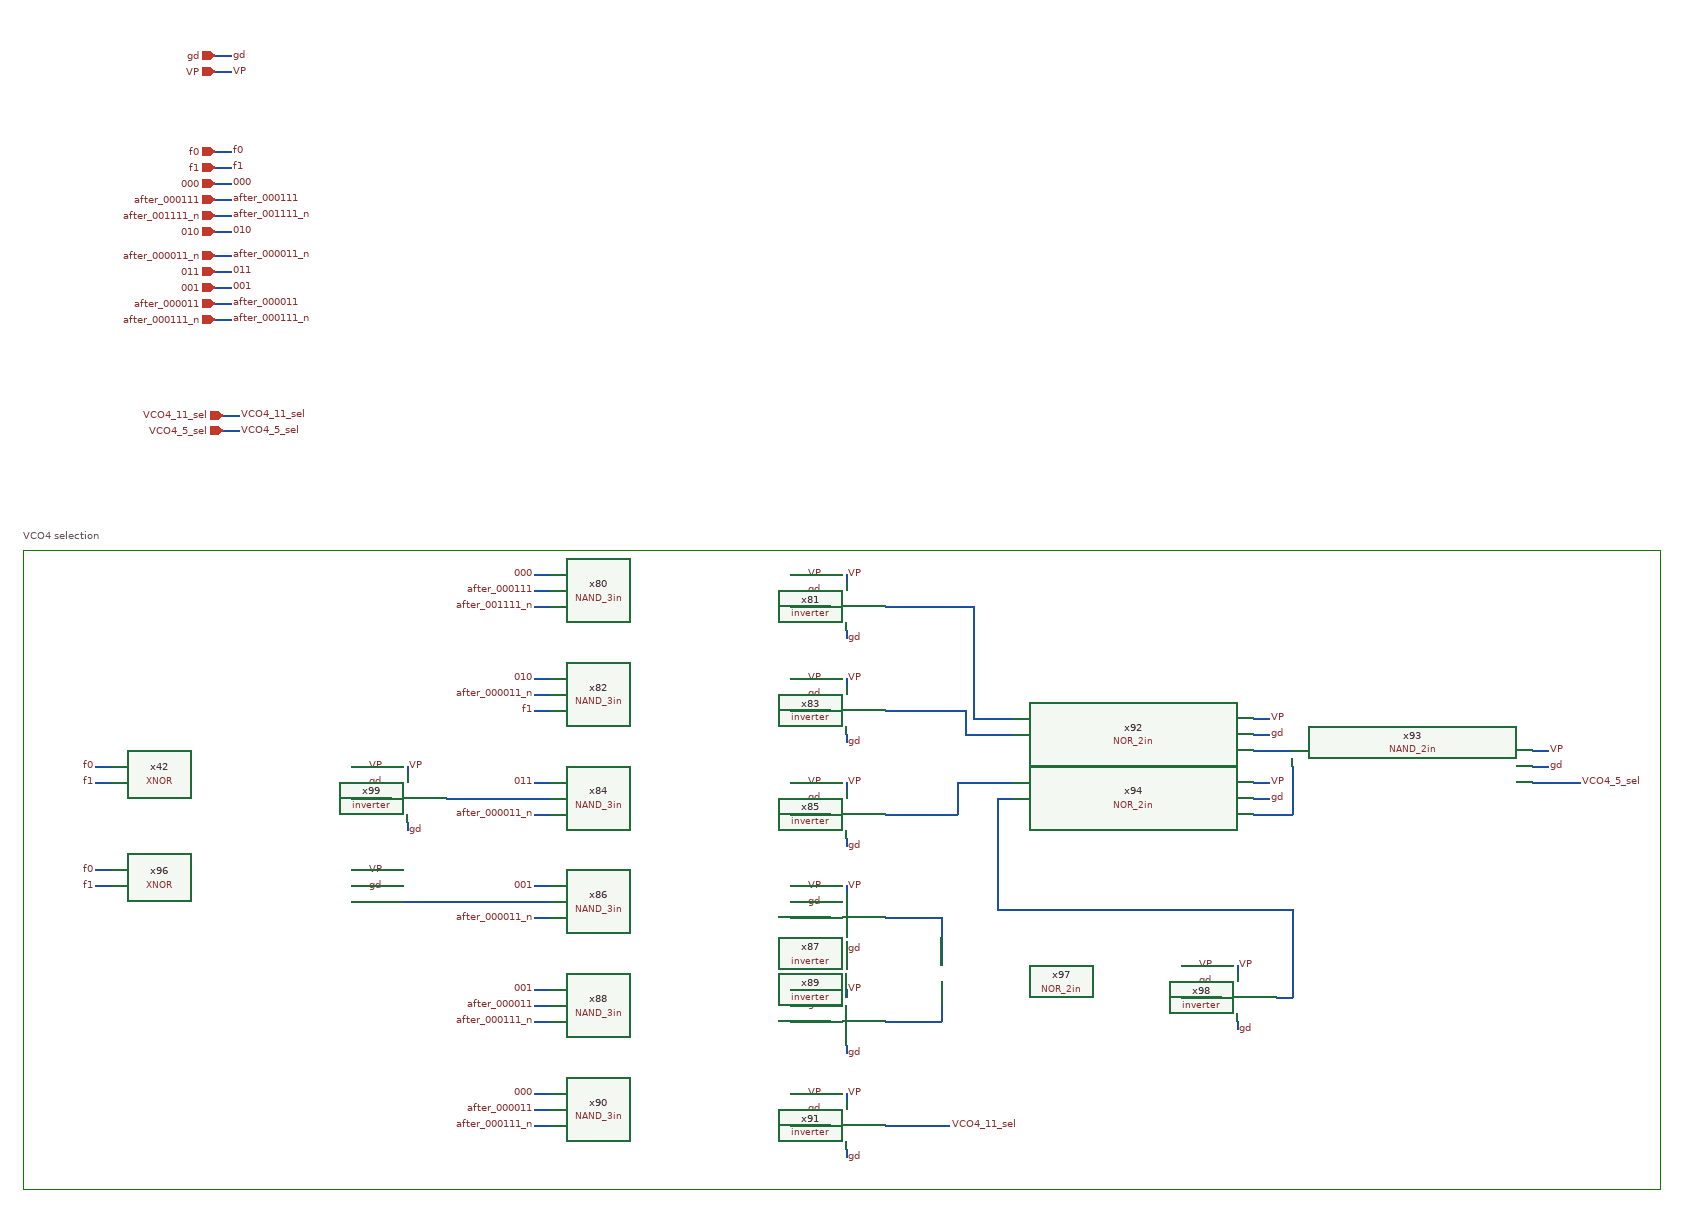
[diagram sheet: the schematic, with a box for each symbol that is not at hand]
v {xschem version=3.4.8RC file_version=1.3}
G {}
K {}
V {}
S {}
F {}
E {}
L 4 1530 -1920 1530 -1580 {}
L 4 1530 -2260 1530 -1920 {}
L 4 1530 -2260 1870 -2260 {}
L 4 1870 -2260 2210 -2260 {}
L 4 2210 -2260 2550 -2260 {}
L 4 2530 -2260 2870 -2260 {}
L 4 2240 -2260 2580 -2260 {}
L 4 2580 -2260 2920 -2260 {}
L 4 2920 -2260 3260 -2260 {}
L 4 3240 -2260 3580 -2260 {}
L 4 1530 -1460 1870 -1460 {}
L 4 1870 -1460 2210 -1460 {}
L 4 2210 -1460 2550 -1460 {}
L 4 2530 -1460 2870 -1460 {}
L 4 2920 -1460 3260 -1460 {}
L 4 3240 -1460 3580 -1460 {}
L 4 2780 -1460 3120 -1460 {}
L 4 1530 -1800 1530 -1460 {}
L 4 3580 -1920 3580 -1580 {}
L 4 3580 -2260 3580 -1920 {}
L 4 3580 -1800 3580 -1460 {}
T {VCO4 selection} 1530 -2290 0 0 0.4 0.4 {}
N 2490 -2210 2510 -2210 {lab=gd}
N 2490 -2230 2510 -2230 {lab=VP}
N 2560 -2160 2560 -2150 {lab=gd}
N 2560 -2230 2560 -2220 {lab=VP}
N 2490 -2190 2540 -2190 {lab=#net1}
N 2610 -2190 2720 -2190 {lab=#net2}
N 2170 -2230 2190 -2230 {lab=000}
N 2170 -2190 2190 -2190 {lab=after_001111_n}
N 2170 -2210 2190 -2210 {lab=after_000111}
N 2490 -2080 2510 -2080 {lab=gd}
N 2490 -2100 2510 -2100 {lab=VP}
N 2560 -2030 2560 -2020 {lab=gd}
N 2560 -2100 2560 -2090 {lab=VP}
N 2490 -2060 2540 -2060 {lab=#net3}
N 2610 -2060 2710 -2060 {lab=#net4}
N 2170 -2100 2190 -2100 {lab=010}
N 2170 -2060 2190 -2060 {lab=f1}
N 2170 -2080 2190 -2080 {lab=after_000011_n}
N 2490 -1950 2510 -1950 {lab=gd}
N 2490 -1970 2510 -1970 {lab=VP}
N 2560 -1900 2560 -1890 {lab=gd}
N 2560 -1970 2560 -1960 {lab=VP}
N 2490 -1930 2540 -1930 {lab=#net5}
N 2610 -1930 2700 -1930 {lab=#net6}
N 2170 -1970 2190 -1970 {lab=011}
N 2170 -1930 2190 -1930 {lab=after_000011_n}
N 2490 -1820 2510 -1820 {lab=gd}
N 2490 -1840 2510 -1840 {lab=VP}
N 2560 -1770 2560 -1760 {lab=gd}
N 2560 -1840 2560 -1830 {lab=VP}
N 2490 -1800 2540 -1800 {lab=#net7}
N 2170 -1840 2190 -1840 {lab=001}
N 2170 -1800 2190 -1800 {lab=after_000011_n}
N 2490 -1690 2510 -1690 {lab=gd}
N 2490 -1710 2510 -1710 {lab=VP}
N 2560 -1640 2560 -1630 {lab=gd}
N 2560 -1710 2560 -1700 {lab=VP}
N 2490 -1670 2540 -1670 {lab=#net8}
N 2170 -1710 2190 -1710 {lab=001}
N 2170 -1670 2190 -1670 {lab=after_000111_n}
N 2170 -1690 2190 -1690 {lab=after_000011}
N 2490 -1560 2510 -1560 {lab=gd}
N 2490 -1580 2510 -1580 {lab=VP}
N 2560 -1510 2560 -1500 {lab=gd}
N 2560 -1580 2560 -1570 {lab=VP}
N 2490 -1540 2540 -1540 {lab=#net9}
N 2610 -1540 2690 -1540 {lab=VCO4_11_sel}
N 2170 -1580 2190 -1580 {lab=000}
N 2170 -1540 2190 -1540 {lab=after_000111_n}
N 2170 -1560 2190 -1560 {lab=after_000011}
N 3070 -2030 3090 -2030 {lab=gd}
N 3070 -2050 3090 -2050 {lab=VP}
N 3070 -2010 3120 -2010 {lab=#net10}
N 3070 -1950 3090 -1950 {lab=gd}
N 3070 -1970 3090 -1970 {lab=VP}
N 3070 -1930 3120 -1930 {lab=#net11}
N 2750 -1950 2770 -1950 {lab=#net12}
N 3120 -1990 3120 -1930 {lab=#net11}
N 3420 -1990 3440 -1990 {lab=gd}
N 3420 -2010 3440 -2010 {lab=VP}
N 2980 -1720 3000 -1720 {lab=gd}
N 2980 -1740 3000 -1740 {lab=VP}
N 3050 -1670 3050 -1660 {lab=gd}
N 3050 -1740 3050 -1730 {lab=VP}
N 2980 -1700 3030 -1700 {lab=#net13}
N 3100 -1700 3120 -1700 {lab=#net12}
N 2680 -1800 2680 -1740 {lab=#net14}
N 2610 -1800 2680 -1800 {lab=#net14}
N 2680 -1720 2680 -1670 {lab=#net15}
N 2610 -1670 2680 -1670 {lab=#net15}
N 2710 -2060 2710 -2030 {lab=#net4}
N 2710 -2030 2770 -2030 {lab=#net4}
N 2720 -2050 2770 -2050 {lab=#net2}
N 2720 -2190 2720 -2050 {lab=#net2}
N 2700 -1970 2700 -1930 {lab=#net6}
N 2700 -1970 2770 -1970 {lab=#net6}
N 2750 -1950 2750 -1810 {lab=#net12}
N 2750 -1810 3120 -1810 {lab=#net12}
N 3120 -1810 3120 -1700 {lab=#net12}
N 3420 -1970 3480 -1970 {lab=VCO4_5_sel}
N 1940 -1840 1960 -1840 {lab=gd}
N 1940 -1860 1960 -1860 {lab=VP}
N 1940 -1970 1960 -1970 {lab=gd}
N 1940 -1990 1960 -1990 {lab=VP}
N 2010 -1920 2010 -1910 {lab=gd}
N 2010 -1990 2010 -1980 {lab=VP}
N 1940 -1950 1990 -1950 {lab=#net16}
N 1620 -1990 1640 -1990 {lab=f0}
N 1620 -1970 1640 -1970 {lab=f1}
N 1940 -1820 2190 -1820 {lab=#net17}
N 2060 -1950 2190 -1950 {lab=#net18}
N 1620 -1860 1640 -1860 {lab=f0}
N 1620 -1840 1640 -1840 {lab=f1}
N 1770 -2880 1790 -2880 {lab=gd}
N 1770 -2860 1790 -2860 {lab=VP}
N 1770 -2760 1790 -2760 {lab=f0}
N 1770 -2740 1790 -2740 {lab=f1}
N 1780 -2410 1800 -2410 {lab=VCO4_5_sel}
N 1780 -2430 1800 -2430 {lab=VCO4_11_sel}
N 1770 -2720 1790 -2720 {lab=000}
N 1770 -2700 1790 -2700 {lab=after_000111}
N 1770 -2680 1790 -2680 {lab=after_001111_n}
N 1770 -2660 1790 -2660 {lab=010}
N 1770 -2630 1790 -2630 {lab=after_000011_n}
N 1770 -2610 1790 -2610 {lab=011}
N 1770 -2590 1790 -2590 {lab=001}
N 1770 -2570 1790 -2570 {lab=after_000011}
N 1770 -2550 1790 -2550 {lab=after_000111_n}
C {NAND_3in.sym} 2340 -2210 0 0 {name=x80}
C {lab_wire.sym} 2510 -2230 2 0 {name=p327 sig_type=std_logic lab=VP}
C {lab_wire.sym} 2510 -2210 2 0 {name=p328 sig_type=std_logic lab=gd}
C {inverter.sym} 2560 -2190 0 0 {name=x81}
C {lab_wire.sym} 2560 -2230 0 1 {name=p329 sig_type=std_logic lab=VP}
C {lab_wire.sym} 2560 -2150 2 0 {name=p330 sig_type=std_logic lab=gd}
C {NAND_3in.sym} 2340 -2080 0 0 {name=x82}
C {lab_wire.sym} 2510 -2100 2 0 {name=p331 sig_type=std_logic lab=VP}
C {lab_wire.sym} 2510 -2080 2 0 {name=p332 sig_type=std_logic lab=gd}
C {inverter.sym} 2560 -2060 0 0 {name=x83}
C {lab_wire.sym} 2560 -2100 0 1 {name=p333 sig_type=std_logic lab=VP}
C {lab_wire.sym} 2560 -2020 2 0 {name=p334 sig_type=std_logic lab=gd}
C {NAND_3in.sym} 2340 -1950 0 0 {name=x84}
C {lab_wire.sym} 2510 -1970 2 0 {name=p335 sig_type=std_logic lab=VP}
C {lab_wire.sym} 2510 -1950 2 0 {name=p336 sig_type=std_logic lab=gd}
C {inverter.sym} 2560 -1930 0 0 {name=x85}
C {lab_wire.sym} 2560 -1970 0 1 {name=p337 sig_type=std_logic lab=VP}
C {lab_wire.sym} 2560 -1890 2 0 {name=p338 sig_type=std_logic lab=gd}
C {NAND_3in.sym} 2340 -1820 0 0 {name=x86}
C {lab_wire.sym} 2510 -1840 2 0 {name=p339 sig_type=std_logic lab=VP}
C {lab_wire.sym} 2510 -1820 2 0 {name=p340 sig_type=std_logic lab=gd}
C {inverter.sym} 2560 -1800 0 0 {name=x87}
C {lab_wire.sym} 2560 -1840 0 1 {name=p341 sig_type=std_logic lab=VP}
C {lab_wire.sym} 2560 -1760 2 0 {name=p342 sig_type=std_logic lab=gd}
C {NAND_3in.sym} 2340 -1690 0 0 {name=x88}
C {lab_wire.sym} 2510 -1710 2 0 {name=p343 sig_type=std_logic lab=VP}
C {lab_wire.sym} 2510 -1690 2 0 {name=p344 sig_type=std_logic lab=gd}
C {inverter.sym} 2560 -1670 0 0 {name=x89}
C {lab_wire.sym} 2560 -1710 0 1 {name=p345 sig_type=std_logic lab=VP}
C {lab_wire.sym} 2560 -1630 2 0 {name=p346 sig_type=std_logic lab=gd}
C {NAND_3in.sym} 2340 -1560 0 0 {name=x90}
C {lab_wire.sym} 2510 -1580 2 0 {name=p347 sig_type=std_logic lab=VP}
C {lab_wire.sym} 2510 -1560 2 0 {name=p348 sig_type=std_logic lab=gd}
C {inverter.sym} 2560 -1540 0 0 {name=x91}
C {lab_wire.sym} 2560 -1580 0 1 {name=p349 sig_type=std_logic lab=VP}
C {lab_wire.sym} 2560 -1500 2 0 {name=p350 sig_type=std_logic lab=gd}
C {NOR_2in.sym} 2920 -2030 0 0 {name=x92}
C {lab_wire.sym} 3090 -2050 2 0 {name=p351 sig_type=std_logic lab=VP}
C {lab_wire.sym} 3090 -2030 2 0 {name=p352 sig_type=std_logic lab=gd}
C {lab_wire.sym} 3090 -1970 2 0 {name=p353 sig_type=std_logic lab=VP}
C {lab_wire.sym} 3090 -1950 2 0 {name=p354 sig_type=std_logic lab=gd}
C {NAND_2in.sym} 3270 -1990 0 0 {name=x93}
C {lab_wire.sym} 3440 -2010 2 0 {name=p355 sig_type=std_logic lab=VP}
C {lab_wire.sym} 3440 -1990 2 0 {name=p356 sig_type=std_logic lab=gd}
C {NOR_2in.sym} 2920 -1950 0 0 {name=x94}
C {NOR_2in.sym} 2830 -1720 0 0 {name=x97}
C {lab_wire.sym} 3000 -1740 2 0 {name=p359 sig_type=std_logic lab=VP}
C {lab_wire.sym} 3000 -1720 2 0 {name=p360 sig_type=std_logic lab=gd}
C {inverter.sym} 3050 -1700 0 0 {name=x98}
C {lab_wire.sym} 3050 -1740 0 1 {name=p361 sig_type=std_logic lab=VP}
C {lab_wire.sym} 3050 -1660 2 0 {name=p362 sig_type=std_logic lab=gd}
C {lab_wire.sym} 2170 -2230 0 0 {name=p357 sig_type=std_logic lab=000}
C {lab_wire.sym} 2170 -2100 0 0 {name=p358 sig_type=std_logic lab=010}
C {lab_wire.sym} 2170 -1970 0 0 {name=p363 sig_type=std_logic lab=011}
C {lab_wire.sym} 2170 -1840 0 0 {name=p364 sig_type=std_logic lab=001}
C {lab_wire.sym} 2170 -1710 0 0 {name=p365 sig_type=std_logic lab=001}
C {lab_wire.sym} 2170 -1580 0 0 {name=p366 sig_type=std_logic lab=000}
C {lab_wire.sym} 2170 -1540 0 0 {name=p367 sig_type=std_logic lab=after_000111_n}
C {lab_wire.sym} 2170 -1560 0 0 {name=p368 sig_type=std_logic lab=after_000011}
C {lab_wire.sym} 2690 -1540 2 0 {name=p369 sig_type=std_logic lab=VCO4_11_sel}
C {lab_wire.sym} 3480 -1970 2 0 {name=p370 sig_type=std_logic lab=VCO4_5_sel}
C {lab_wire.sym} 2170 -2190 0 0 {name=p371 sig_type=std_logic lab=after_001111_n}
C {lab_wire.sym} 2170 -2210 0 0 {name=p372 sig_type=std_logic lab=after_000111}
C {lab_wire.sym} 2170 -2080 0 0 {name=p373 sig_type=std_logic lab=after_000011_n}
C {lab_wire.sym} 2170 -2060 0 0 {name=p374 sig_type=std_logic lab=f1}
C {lab_wire.sym} 2170 -1690 0 0 {name=p375 sig_type=std_logic lab=after_000011}
C {lab_wire.sym} 2170 -1670 0 0 {name=p376 sig_type=std_logic lab=after_000111_n}
C {lab_wire.sym} 2170 -1800 0 0 {name=p377 sig_type=std_logic lab=after_000011_n}
C {lab_wire.sym} 2170 -1930 0 0 {name=p378 sig_type=std_logic lab=after_000011_n}
C {XNOR.sym} 1790 -1840 0 0 {name=x96}
C {lab_wire.sym} 1960 -1860 2 0 {name=p379 sig_type=std_logic lab=VP}
C {lab_wire.sym} 1960 -1840 2 0 {name=p380 sig_type=std_logic lab=gd}
C {lab_wire.sym} 1960 -1990 2 0 {name=p381 sig_type=std_logic lab=VP}
C {lab_wire.sym} 1960 -1970 2 0 {name=p382 sig_type=std_logic lab=gd}
C {inverter.sym} 2010 -1950 0 0 {name=x99}
C {lab_wire.sym} 2010 -1990 0 1 {name=p383 sig_type=std_logic lab=VP}
C {lab_wire.sym} 2010 -1910 2 0 {name=p384 sig_type=std_logic lab=gd}
C {lab_wire.sym} 1620 -1990 0 0 {name=p385 sig_type=std_logic lab=f0}
C {lab_wire.sym} 1620 -1860 0 0 {name=p386 sig_type=std_logic lab=f0}
C {lab_wire.sym} 1620 -1970 0 0 {name=p387 sig_type=std_logic lab=f1}
C {lab_wire.sym} 1620 -1840 0 0 {name=p388 sig_type=std_logic lab=f1}
C {XNOR.sym} 1790 -1970 0 0 {name=x42}
C {iopin.sym} 1770 -2880 2 0 {name=p46 lab=gd}
C {lab_wire.sym} 1790 -2880 2 0 {name=p53 sig_type=std_logic lab=gd}
C {iopin.sym} 1770 -2860 2 0 {name=p54 lab=VP}
C {ipin.sym} 1770 -2760 0 0 {name=p59 lab=f0}
C {lab_wire.sym} 1790 -2760 2 0 {name=p60 sig_type=std_logic lab=f0}
C {ipin.sym} 1770 -2740 0 0 {name=p61 lab=f1}
C {lab_wire.sym} 1790 -2740 2 0 {name=p63 sig_type=std_logic lab=f1}
C {lab_wire.sym} 1790 -2860 2 0 {name=p1 sig_type=std_logic lab=VP}
C {opin.sym} 1780 -2410 0 1 {name=p6 lab=VCO4_5_sel}
C {lab_wire.sym} 1800 -2410 2 0 {name=p7 sig_type=std_logic lab=VCO4_5_sel}
C {opin.sym} 1780 -2430 0 1 {name=p14 lab=VCO4_11_sel}
C {lab_wire.sym} 1800 -2430 2 0 {name=p15 sig_type=std_logic lab=VCO4_11_sel}
C {ipin.sym} 1770 -2720 0 0 {name=p19 lab=000
}
C {lab_wire.sym} 1790 -2720 2 0 {name=p22 sig_type=std_logic lab=000}
C {ipin.sym} 1770 -2700 0 0 {name=p23 lab=after_000111}
C {lab_wire.sym} 1790 -2700 2 0 {name=p24 sig_type=std_logic lab=after_000111}
C {ipin.sym} 1770 -2680 0 0 {name=p25 lab=after_001111_n}
C {lab_wire.sym} 1790 -2680 2 0 {name=p26 sig_type=std_logic lab=after_001111_n}
C {ipin.sym} 1770 -2660 0 0 {name=p27 lab=010}
C {lab_wire.sym} 1790 -2660 2 0 {name=p28 sig_type=std_logic lab=010}
C {ipin.sym} 1770 -2630 0 0 {name=p2 lab=after_000011_n}
C {lab_wire.sym} 1790 -2630 2 0 {name=p3 sig_type=std_logic lab=after_000011_n}
C {ipin.sym} 1770 -2610 0 0 {name=p4 lab=011}
C {lab_wire.sym} 1790 -2610 2 0 {name=p5 sig_type=std_logic lab=011}
C {ipin.sym} 1770 -2590 0 0 {name=p8 lab=001
}
C {lab_wire.sym} 1790 -2590 2 0 {name=p9 sig_type=std_logic lab=001}
C {ipin.sym} 1770 -2570 0 0 {name=p10 lab=after_000011}
C {lab_wire.sym} 1790 -2570 2 0 {name=p11 sig_type=std_logic lab=after_000011}
C {ipin.sym} 1770 -2550 0 0 {name=p12 lab=after_000111_n}
C {lab_wire.sym} 1790 -2550 2 0 {name=p13 sig_type=std_logic lab=after_000111_n}
